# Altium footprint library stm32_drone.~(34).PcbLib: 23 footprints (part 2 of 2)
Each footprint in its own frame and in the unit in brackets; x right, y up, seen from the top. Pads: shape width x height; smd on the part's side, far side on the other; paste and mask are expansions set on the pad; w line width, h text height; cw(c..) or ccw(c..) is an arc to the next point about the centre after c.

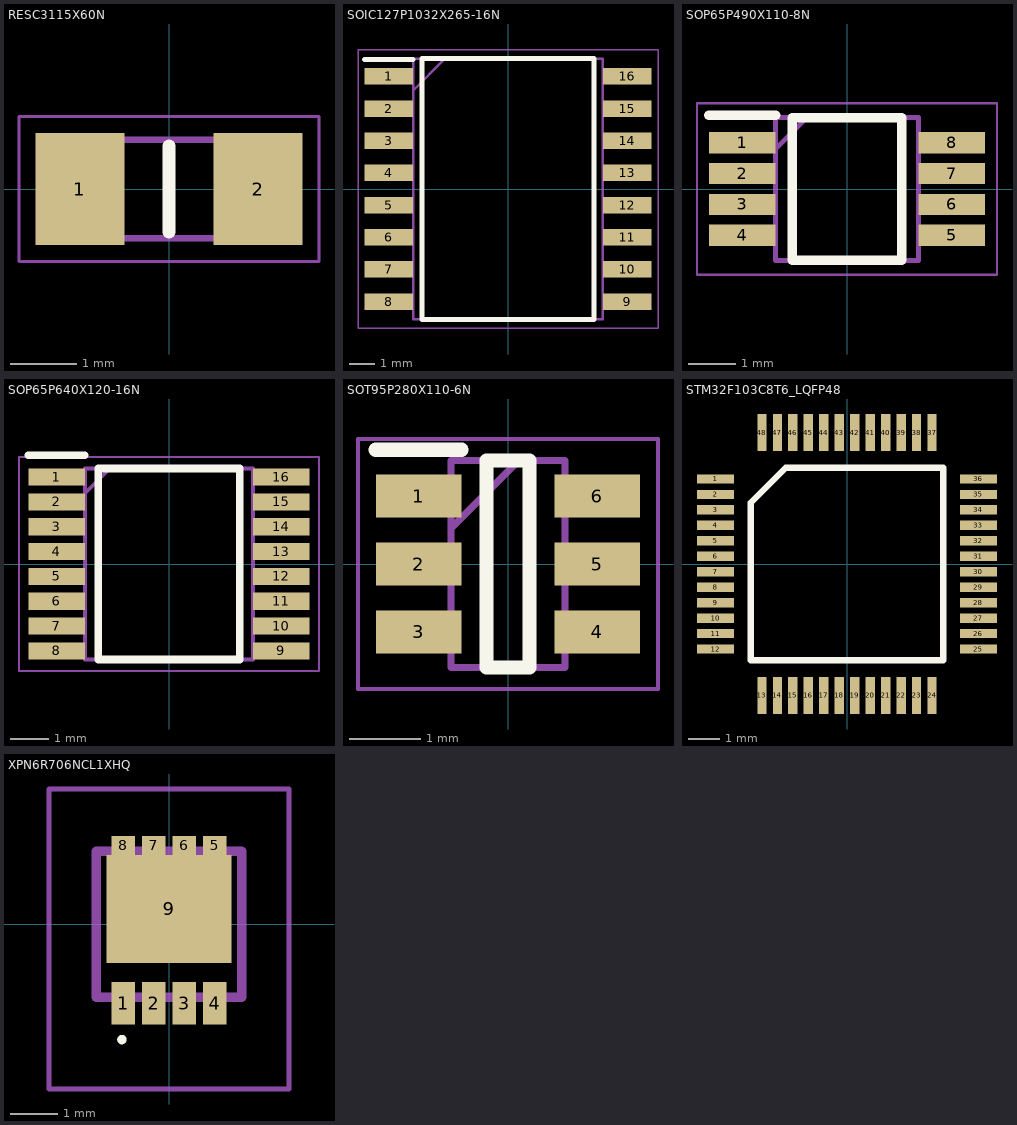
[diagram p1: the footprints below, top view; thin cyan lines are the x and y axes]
## RESC3115X60N [mm]
pads (2):
  rect 1.35x1.7 smd: 1(-1.35,0) 2(1.35,0)
Top Overlay:
  lines w0.2: 0,-0.65 0,0.65
Mechanical 13:
  lines w0.1: -1.55,-0.75 1.55,-0.75 1.55,0.75 -1.55,0.75 -1.55,-0.75
Mechanical 15:
  lines w0.05: -2.275,-1.1 2.275,-1.1 2.275,1.1 -2.275,1.1 -2.275,-1.1
3D body "RNCP1206FTD10K0.stp": height 0.5, standoff 0, extent -1.554,-0.746 1.546,0.754

## SOIC127P1032X265-16N [mm]
pads (16):
  rect 1.925x0.65 smd: 1(-4.712,4.445) 2(-4.712,3.175) 3(-4.712,1.905) 4(-4.712,0.635) 5(-4.712,-0.635) 6(-4.712,-1.905) 7(-4.712,-3.175) 8(-4.712,-4.445) 9(4.712,-4.445) 10(4.712,-3.175) 11(4.712,-1.905) 12(4.712,-0.635) 13(4.712,0.635) 14(4.712,1.905) 15(4.712,3.175) 16(4.712,4.445)
Top Overlay:
  lines w0.2: -5.675,5.12 -3.75,5.12 ; -3.4,-5.15 -3.4,5.15 3.4,5.15 3.4,-5.15 -3.4,-5.15
Mechanical 13:
  lines w0.1: -3.75,3.88 -2.48,5.15 ; -3.75,-5.15 -3.75,5.15 3.75,5.15 3.75,-5.15 -3.75,-5.15
Mechanical 15:
  lines w0.05: -5.925,-5.5 -5.925,5.5 5.925,5.5 5.925,-5.5 -5.925,-5.5
3D body "IR2110STRPBF.stp": height 2.65, standoff 0, extent -5.162,-5.15 5.162,5.15

## SOP65P490X110-8N [mm]
pads (8):
  rect 1.4x0.45 smd: 1(-2.2,0.975) 2(-2.2,0.325) 3(-2.2,-0.325) 4(-2.2,-0.975) 5(2.2,-0.975) 6(2.2,-0.325) 7(2.2,0.325) 8(2.2,0.975)
Top Overlay:
  lines w0.2: -2.9,1.55 -1.5,1.55 ; -1.15,-1.5 -1.15,1.5 1.15,1.5 1.15,-1.5 -1.15,-1.5
Mechanical 13:
  lines w0.1: -1.5,0.85 -0.85,1.5 ; -1.5,-1.5 -1.5,1.5 1.5,1.5 1.5,-1.5 -1.5,-1.5
Mechanical 15:
  lines w0.05: -3.15,-1.8 -3.15,1.8 3.15,1.8 3.15,-1.8 -3.15,-1.8
3D body "LM3485MMX_NOPB.stp": height 1.1, standoff 0, extent -2.451,-1.499 2.451,1.499

## SOP65P640X120-16N [mm]
pads (16):
  rect 1.475x0.45 smd: 1(-2.938,2.275) 2(-2.938,1.625) 3(-2.938,0.975) 4(-2.938,0.325) 5(-2.938,-0.325) 6(-2.938,-0.975) 7(-2.938,-1.625) 8(-2.938,-2.275) 9(2.938,-2.275) 10(2.938,-1.625) 11(2.938,-0.975) 12(2.938,-0.325) 13(2.938,0.325) 14(2.938,0.975) 15(2.938,1.625) 16(2.938,2.275)
Top Overlay:
  lines w0.2: -3.675,2.85 -2.2,2.85 ; -1.85,-2.5 -1.85,2.5 1.85,2.5 1.85,-2.5 -1.85,-2.5
Mechanical 13:
  lines w0.1: -2.2,1.85 -1.55,2.5 ; -2.2,-2.5 -2.2,2.5 2.2,2.5 2.2,-2.5 -2.2,-2.5
Mechanical 15:
  lines w0.05: -3.925,-2.8 -3.925,2.8 3.925,2.8 3.925,-2.8 -3.925,-2.8
3D body "MIC4606-2YTS-TR.stp": height 1.2, standoff 0, extent -3.2,-2.5 3.2,2.5

## SOT95P280X110-6N [mm]
pads (6):
  rect 1.2x0.6 smd: 1(-1.25,0.95) 2(-1.25,0) 3(-1.25,-0.95) 4(1.25,-0.95) 5(1.25,0) 6(1.25,0.95)
Top Overlay:
  lines w0.2: -1.85,1.6 -0.65,1.6 ; -0.3,-1.45 0.3,-1.45 0.3,1.45 -0.3,1.45 -0.3,-1.45
Mechanical 13:
  lines w0.1: -0.8,0.5 0.15,1.45 ; -0.8,-1.45 0.8,-1.45 0.8,1.45 -0.8,1.45 -0.8,-1.45
Mechanical 15:
  lines w0.05: -2.1,-1.75 2.1,-1.75 2.1,1.75 -2.1,1.75 -2.1,-1.75
3D body "FDC5614P.stp": height 1.1, standoff 0, extent -1.4,-1.45 1.4,1.45

## STM32F103C8T6_LQFP48 [mm]
pads (48):
  rect 1.2x0.3 smd mask+0.05: 1(-4.25,2.75) 2(-4.25,2.25) 3(-4.25,1.75) 4(-4.25,1.25) 5(-4.25,0.75) 6(-4.25,0.25) 7(-4.25,-0.25) 8(-4.25,-0.75) 9(-4.25,-1.25) 10(-4.25,-1.75) 11(-4.25,-2.25) 12(-4.25,-2.75) 25(4.25,-2.75) 26(4.25,-2.25) 27(4.25,-1.75) 28(4.25,-1.25) 29(4.25,-0.75) 30(4.25,-0.25) 31(4.25,0.25) 32(4.25,0.75) 33(4.25,1.25) 34(4.25,1.75) 35(4.25,2.25) 36(4.25,2.75)
  rect 0.3x1.2 smd mask+0.05: 13(-2.75,-4.25) 14(-2.25,-4.25) 15(-1.75,-4.25) 16(-1.25,-4.25) 17(-0.75,-4.25) 18(-0.25,-4.25) 19(0.25,-4.25) 20(0.75,-4.25) 21(1.25,-4.25) 22(1.75,-4.25) 23(2.25,-4.25) 24(2.75,-4.25) 37(2.75,4.25) 38(2.25,4.25) 39(1.75,4.25) 40(1.25,4.25) 41(0.75,4.25) 42(0.25,4.25) 43(-0.25,4.25) 44(-0.75,4.25) 45(-1.25,4.25) 46(-1.75,4.25) 47(-2.25,4.25) 48(-2.75,4.25)
Top Overlay:
  lines w0.2: -3.115,-3.115 -3.115,1.98 -1.98,3.115 3.115,3.115 3.115,-3.115 -3.115,-3.115
3D body "LQFP48_STM.step": height 1.6, standoff 0, extent -4.597,-4.597 4.597,4.597

## XPN6R706NCL1XHQ [mm]
pads (9):
  rect 0.5x0.9 smd mask+0.001: 1(-0.975,-1.675) 2(-0.325,-1.675) 3(0.325,-1.675) 4(0.975,-1.675)
  rect 0.5x0.4 smd mask+0.001: 5(0.975,1.675) 6(0.325,1.675) 7(-0.325,1.675) 8(-0.975,1.675)
  rect 2.65x2.3 smd mask+0.001: 9(0,0.325)
Top Overlay:
  lines w0.1: -1,-2.5 ccw(c-1,-2.45) -1,-2.4 ccw(c-1,-2.45) -1,-2.5
Mechanical 13:
  lines w0.2: -1.55,-1.55 -1.55,1.55 1.55,1.55 1.55,-1.55 -1.55,-1.55
Mechanical 15:
  lines w0.1: -2.55,-3.5 -2.55,2.875 2.55,2.875 2.55,-3.5 -2.55,-3.5
3D body "XPN6R706NC,L1XHQ.stp": height 1, standoff 0, extent -1.55,-2.075 1.55,1.835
